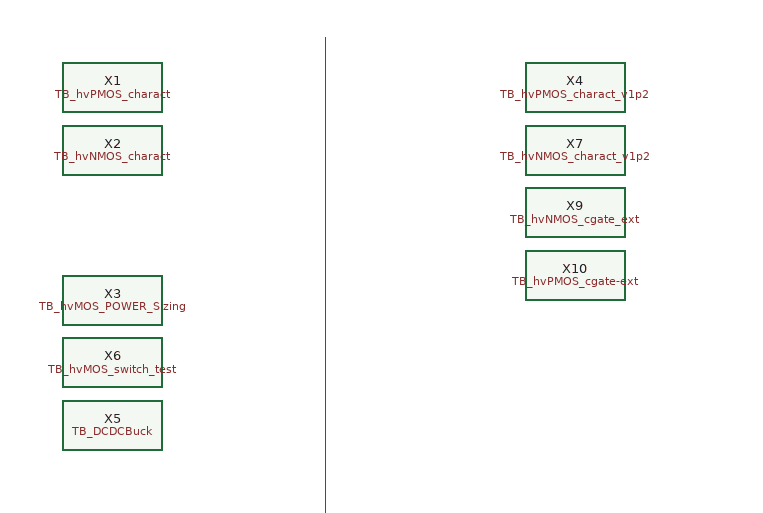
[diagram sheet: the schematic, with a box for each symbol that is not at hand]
v {xschem version=3.4.5 file_version=1.2
}
G {}
K {}
V {}
S {}
E {}
L 4 -4390 -790 -4390 -410 {}
L 4 -4030 -790 -4030 -400 {}
L 4 -4390 -410 -4390 -400 {}
C {TB_hvPMOS_charact.sym} -4200 -750 0 0 {name=X1}
C {TB_hvNMOS_charact.sym} -4200 -700 0 0 {name=X2}
C {TB_hvMOS_POWER_Sizing.sym} -4200 -580 0 0 {name=X3}
C {TB_DCDCBuck.sym} -4200 -480 0 0 {name=X5}
C {title.sym} -4260 -330 0 0 {name=l1 author="Andrés Martínez"}
C {TB_hvMOS_switch_test.sym} -4200 -530 0 0 {name=X6}
C {TB_hvPMOS_charact_v1p2.sym} -3830 -750 0 0 {name=X4}
C {TB_hvNMOS_charact_v1p2.sym} -3830 -700 0 0 {name=X7}
C {/workspaces/usm-vlsi-tools/Workshop-CANELOS24/xschem/TB_hvPMOS_cgate-ext.sym} -3830 -600 0 0 {name=X10}
C {/workspaces/usm-vlsi-tools/Workshop-CANELOS24/xschem/TB_hvNMOS_cgate_ext.sym} -3830 -650 0 0 {name=X9}
